VERSION 5.7 ;
  NOWIREEXTENSIONATPIN ON ;
  DIVIDERCHAR "/" ;
  BUSBITCHARS "[]" ;
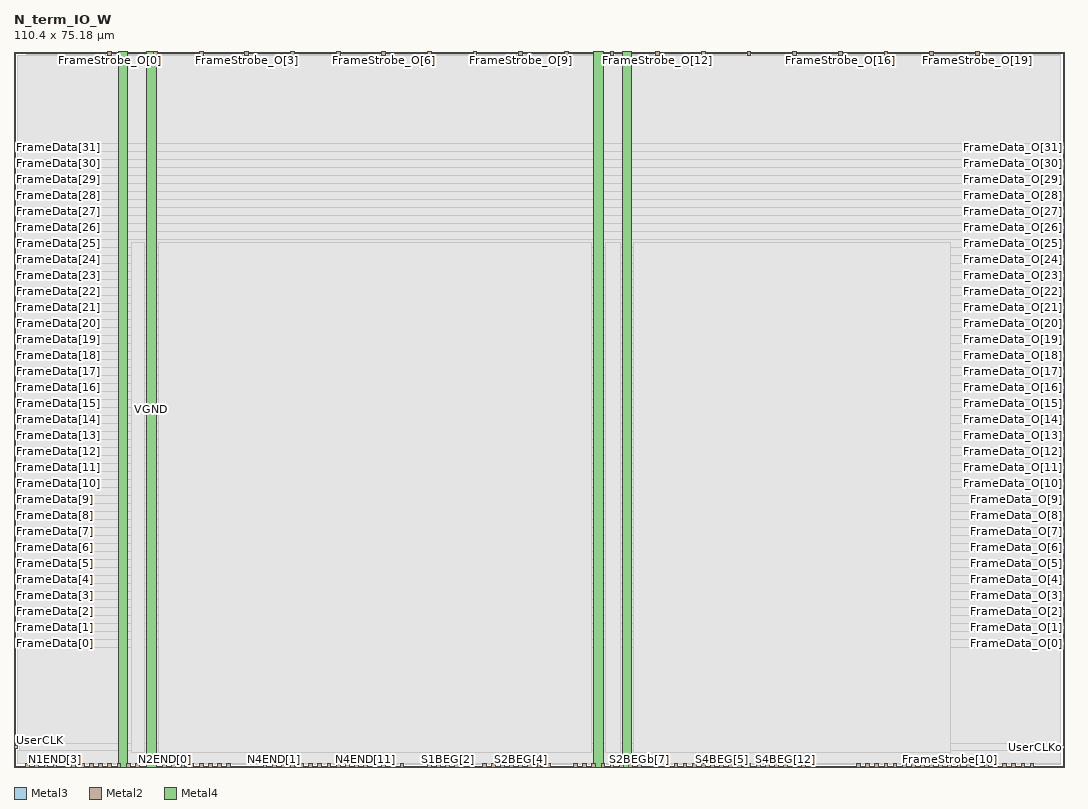
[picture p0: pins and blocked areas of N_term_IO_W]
MACRO N_term_IO_W
  CLASS BLOCK ;
  FOREIGN N_term_IO_W ;
  ORIGIN 0.000 0.000 ;
  SIZE 110.400 BY 75.180 ;
  PIN FrameData[0]
    DIRECTION INPUT ;
    USE SIGNAL ;
    ANTENNAGATEAREA 0.180700 ;
    ANTENNADIFFAREA 2.015400 ;
    PORT
      LAYER Metal3 ;
        RECT 0.000 12.820 0.400 13.220 ;
    END
  END FrameData[0]
  PIN FrameData[10]
    DIRECTION INPUT ;
    USE SIGNAL ;
    ANTENNAGATEAREA 0.180700 ;
    ANTENNADIFFAREA 2.015400 ;
    PORT
      LAYER Metal3 ;
        RECT 0.000 29.620 0.400 30.020 ;
    END
  END FrameData[10]
  PIN FrameData[11]
    DIRECTION INPUT ;
    USE SIGNAL ;
    ANTENNAGATEAREA 0.180700 ;
    ANTENNADIFFAREA 2.015400 ;
    PORT
      LAYER Metal3 ;
        RECT 0.000 31.300 0.400 31.700 ;
    END
  END FrameData[11]
  PIN FrameData[12]
    DIRECTION INPUT ;
    USE SIGNAL ;
    ANTENNAGATEAREA 0.180700 ;
    ANTENNADIFFAREA 2.015400 ;
    PORT
      LAYER Metal3 ;
        RECT 0.000 32.980 0.400 33.380 ;
    END
  END FrameData[12]
  PIN FrameData[13]
    DIRECTION INPUT ;
    USE SIGNAL ;
    ANTENNAGATEAREA 0.180700 ;
    ANTENNADIFFAREA 2.015400 ;
    PORT
      LAYER Metal3 ;
        RECT 0.000 34.660 0.400 35.060 ;
    END
  END FrameData[13]
  PIN FrameData[14]
    DIRECTION INPUT ;
    USE SIGNAL ;
    ANTENNAGATEAREA 0.180700 ;
    ANTENNADIFFAREA 2.015400 ;
    PORT
      LAYER Metal3 ;
        RECT 0.000 36.340 0.400 36.740 ;
    END
  END FrameData[14]
  PIN FrameData[15]
    DIRECTION INPUT ;
    USE SIGNAL ;
    ANTENNAGATEAREA 0.180700 ;
    ANTENNADIFFAREA 2.015400 ;
    PORT
      LAYER Metal3 ;
        RECT 0.000 38.020 0.400 38.420 ;
    END
  END FrameData[15]
  PIN FrameData[16]
    DIRECTION INPUT ;
    USE SIGNAL ;
    ANTENNAGATEAREA 0.180700 ;
    ANTENNADIFFAREA 2.015400 ;
    PORT
      LAYER Metal3 ;
        RECT 0.000 39.700 0.400 40.100 ;
    END
  END FrameData[16]
  PIN FrameData[17]
    DIRECTION INPUT ;
    USE SIGNAL ;
    ANTENNAGATEAREA 0.180700 ;
    ANTENNADIFFAREA 2.015400 ;
    PORT
      LAYER Metal3 ;
        RECT 0.000 41.380 0.400 41.780 ;
    END
  END FrameData[17]
  PIN FrameData[18]
    DIRECTION INPUT ;
    USE SIGNAL ;
    ANTENNAGATEAREA 0.180700 ;
    ANTENNADIFFAREA 2.015400 ;
    PORT
      LAYER Metal3 ;
        RECT 0.000 43.060 0.400 43.460 ;
    END
  END FrameData[18]
  PIN FrameData[19]
    DIRECTION INPUT ;
    USE SIGNAL ;
    ANTENNAGATEAREA 0.180700 ;
    ANTENNADIFFAREA 2.015400 ;
    PORT
      LAYER Metal3 ;
        RECT 0.000 44.740 0.400 45.140 ;
    END
  END FrameData[19]
  PIN FrameData[1]
    DIRECTION INPUT ;
    USE SIGNAL ;
    ANTENNAGATEAREA 0.180700 ;
    ANTENNADIFFAREA 2.015400 ;
    PORT
      LAYER Metal3 ;
        RECT 0.000 14.500 0.400 14.900 ;
    END
  END FrameData[1]
  PIN FrameData[20]
    DIRECTION INPUT ;
    USE SIGNAL ;
    ANTENNAGATEAREA 0.180700 ;
    ANTENNADIFFAREA 2.015400 ;
    PORT
      LAYER Metal3 ;
        RECT 0.000 46.420 0.400 46.820 ;
    END
  END FrameData[20]
  PIN FrameData[21]
    DIRECTION INPUT ;
    USE SIGNAL ;
    ANTENNAGATEAREA 0.180700 ;
    ANTENNADIFFAREA 2.015400 ;
    PORT
      LAYER Metal3 ;
        RECT 0.000 48.100 0.400 48.500 ;
    END
  END FrameData[21]
  PIN FrameData[22]
    DIRECTION INPUT ;
    USE SIGNAL ;
    ANTENNAGATEAREA 0.180700 ;
    ANTENNADIFFAREA 2.015400 ;
    PORT
      LAYER Metal3 ;
        RECT 0.000 49.780 0.400 50.180 ;
    END
  END FrameData[22]
  PIN FrameData[23]
    DIRECTION INPUT ;
    USE SIGNAL ;
    ANTENNAGATEAREA 0.180700 ;
    ANTENNADIFFAREA 2.015400 ;
    PORT
      LAYER Metal3 ;
        RECT 0.000 51.460 0.400 51.860 ;
    END
  END FrameData[23]
  PIN FrameData[24]
    DIRECTION INPUT ;
    USE SIGNAL ;
    ANTENNAGATEAREA 0.180700 ;
    ANTENNADIFFAREA 2.015400 ;
    PORT
      LAYER Metal3 ;
        RECT 0.000 53.140 0.400 53.540 ;
    END
  END FrameData[24]
  PIN FrameData[25]
    DIRECTION INPUT ;
    USE SIGNAL ;
    ANTENNAGATEAREA 0.180700 ;
    ANTENNADIFFAREA 2.015400 ;
    PORT
      LAYER Metal3 ;
        RECT 0.000 54.820 0.400 55.220 ;
    END
  END FrameData[25]
  PIN FrameData[26]
    DIRECTION INPUT ;
    USE SIGNAL ;
    ANTENNAGATEAREA 0.180700 ;
    ANTENNADIFFAREA 2.015400 ;
    PORT
      LAYER Metal3 ;
        RECT 0.000 56.500 0.400 56.900 ;
    END
  END FrameData[26]
  PIN FrameData[27]
    DIRECTION INPUT ;
    USE SIGNAL ;
    ANTENNAGATEAREA 0.180700 ;
    ANTENNADIFFAREA 2.015400 ;
    PORT
      LAYER Metal3 ;
        RECT 0.000 58.180 0.400 58.580 ;
    END
  END FrameData[27]
  PIN FrameData[28]
    DIRECTION INPUT ;
    USE SIGNAL ;
    ANTENNAGATEAREA 0.180700 ;
    ANTENNADIFFAREA 2.015400 ;
    PORT
      LAYER Metal3 ;
        RECT 0.000 59.860 0.400 60.260 ;
    END
  END FrameData[28]
  PIN FrameData[29]
    DIRECTION INPUT ;
    USE SIGNAL ;
    ANTENNAGATEAREA 0.180700 ;
    ANTENNADIFFAREA 2.015400 ;
    PORT
      LAYER Metal3 ;
        RECT 0.000 61.540 0.400 61.940 ;
    END
  END FrameData[29]
  PIN FrameData[2]
    DIRECTION INPUT ;
    USE SIGNAL ;
    ANTENNAGATEAREA 0.180700 ;
    ANTENNADIFFAREA 2.015400 ;
    PORT
      LAYER Metal3 ;
        RECT 0.000 16.180 0.400 16.580 ;
    END
  END FrameData[2]
  PIN FrameData[30]
    DIRECTION INPUT ;
    USE SIGNAL ;
    ANTENNAGATEAREA 0.180700 ;
    ANTENNADIFFAREA 2.015400 ;
    PORT
      LAYER Metal3 ;
        RECT 0.000 63.220 0.400 63.620 ;
    END
  END FrameData[30]
  PIN FrameData[31]
    DIRECTION INPUT ;
    USE SIGNAL ;
    ANTENNAGATEAREA 0.180700 ;
    ANTENNADIFFAREA 2.015400 ;
    PORT
      LAYER Metal3 ;
        RECT 0.000 64.900 0.400 65.300 ;
    END
  END FrameData[31]
  PIN FrameData[3]
    DIRECTION INPUT ;
    USE SIGNAL ;
    ANTENNAGATEAREA 0.180700 ;
    ANTENNADIFFAREA 2.015400 ;
    PORT
      LAYER Metal3 ;
        RECT 0.000 17.860 0.400 18.260 ;
    END
  END FrameData[3]
  PIN FrameData[4]
    DIRECTION INPUT ;
    USE SIGNAL ;
    ANTENNAGATEAREA 0.180700 ;
    ANTENNADIFFAREA 2.015400 ;
    PORT
      LAYER Metal3 ;
        RECT 0.000 19.540 0.400 19.940 ;
    END
  END FrameData[4]
  PIN FrameData[5]
    DIRECTION INPUT ;
    USE SIGNAL ;
    ANTENNAGATEAREA 0.180700 ;
    ANTENNADIFFAREA 2.015400 ;
    PORT
      LAYER Metal3 ;
        RECT 0.000 21.220 0.400 21.620 ;
    END
  END FrameData[5]
  PIN FrameData[6]
    DIRECTION INPUT ;
    USE SIGNAL ;
    ANTENNAGATEAREA 0.180700 ;
    ANTENNADIFFAREA 2.015400 ;
    PORT
      LAYER Metal3 ;
        RECT 0.000 22.900 0.400 23.300 ;
    END
  END FrameData[6]
  PIN FrameData[7]
    DIRECTION INPUT ;
    USE SIGNAL ;
    ANTENNAGATEAREA 0.180700 ;
    ANTENNADIFFAREA 2.015400 ;
    PORT
      LAYER Metal3 ;
        RECT 0.000 24.580 0.400 24.980 ;
    END
  END FrameData[7]
  PIN FrameData[8]
    DIRECTION INPUT ;
    USE SIGNAL ;
    ANTENNAGATEAREA 0.180700 ;
    ANTENNADIFFAREA 2.015400 ;
    PORT
      LAYER Metal3 ;
        RECT 0.000 26.260 0.400 26.660 ;
    END
  END FrameData[8]
  PIN FrameData[9]
    DIRECTION INPUT ;
    USE SIGNAL ;
    ANTENNAGATEAREA 0.180700 ;
    ANTENNADIFFAREA 2.015400 ;
    PORT
      LAYER Metal3 ;
        RECT 0.000 27.940 0.400 28.340 ;
    END
  END FrameData[9]
  PIN FrameData_O[0]
    DIRECTION OUTPUT ;
    USE SIGNAL ;
    ANTENNADIFFAREA 2.724000 ;
    PORT
      LAYER Metal3 ;
        RECT 110.000 12.820 110.400 13.220 ;
    END
  END FrameData_O[0]
  PIN FrameData_O[10]
    DIRECTION OUTPUT ;
    USE SIGNAL ;
    ANTENNADIFFAREA 2.724000 ;
    PORT
      LAYER Metal3 ;
        RECT 110.000 29.620 110.400 30.020 ;
    END
  END FrameData_O[10]
  PIN FrameData_O[11]
    DIRECTION OUTPUT ;
    USE SIGNAL ;
    ANTENNADIFFAREA 2.724000 ;
    PORT
      LAYER Metal3 ;
        RECT 110.000 31.300 110.400 31.700 ;
    END
  END FrameData_O[11]
  PIN FrameData_O[12]
    DIRECTION OUTPUT ;
    USE SIGNAL ;
    ANTENNADIFFAREA 2.724000 ;
    PORT
      LAYER Metal3 ;
        RECT 110.000 32.980 110.400 33.380 ;
    END
  END FrameData_O[12]
  PIN FrameData_O[13]
    DIRECTION OUTPUT ;
    USE SIGNAL ;
    ANTENNADIFFAREA 2.724000 ;
    PORT
      LAYER Metal3 ;
        RECT 110.000 34.660 110.400 35.060 ;
    END
  END FrameData_O[13]
  PIN FrameData_O[14]
    DIRECTION OUTPUT ;
    USE SIGNAL ;
    ANTENNADIFFAREA 2.724000 ;
    PORT
      LAYER Metal3 ;
        RECT 110.000 36.340 110.400 36.740 ;
    END
  END FrameData_O[14]
  PIN FrameData_O[15]
    DIRECTION OUTPUT ;
    USE SIGNAL ;
    ANTENNADIFFAREA 2.724000 ;
    PORT
      LAYER Metal3 ;
        RECT 110.000 38.020 110.400 38.420 ;
    END
  END FrameData_O[15]
  PIN FrameData_O[16]
    DIRECTION OUTPUT ;
    USE SIGNAL ;
    ANTENNADIFFAREA 2.724000 ;
    PORT
      LAYER Metal3 ;
        RECT 110.000 39.700 110.400 40.100 ;
    END
  END FrameData_O[16]
  PIN FrameData_O[17]
    DIRECTION OUTPUT ;
    USE SIGNAL ;
    ANTENNADIFFAREA 2.724000 ;
    PORT
      LAYER Metal3 ;
        RECT 110.000 41.380 110.400 41.780 ;
    END
  END FrameData_O[17]
  PIN FrameData_O[18]
    DIRECTION OUTPUT ;
    USE SIGNAL ;
    ANTENNADIFFAREA 2.724000 ;
    PORT
      LAYER Metal3 ;
        RECT 110.000 43.060 110.400 43.460 ;
    END
  END FrameData_O[18]
  PIN FrameData_O[19]
    DIRECTION OUTPUT ;
    USE SIGNAL ;
    ANTENNADIFFAREA 2.724000 ;
    PORT
      LAYER Metal3 ;
        RECT 110.000 44.740 110.400 45.140 ;
    END
  END FrameData_O[19]
  PIN FrameData_O[1]
    DIRECTION OUTPUT ;
    USE SIGNAL ;
    ANTENNADIFFAREA 2.724000 ;
    PORT
      LAYER Metal3 ;
        RECT 110.000 14.500 110.400 14.900 ;
    END
  END FrameData_O[1]
  PIN FrameData_O[20]
    DIRECTION OUTPUT ;
    USE SIGNAL ;
    ANTENNADIFFAREA 2.724000 ;
    PORT
      LAYER Metal3 ;
        RECT 110.000 46.420 110.400 46.820 ;
    END
  END FrameData_O[20]
  PIN FrameData_O[21]
    DIRECTION OUTPUT ;
    USE SIGNAL ;
    ANTENNADIFFAREA 2.724000 ;
    PORT
      LAYER Metal3 ;
        RECT 110.000 48.100 110.400 48.500 ;
    END
  END FrameData_O[21]
  PIN FrameData_O[22]
    DIRECTION OUTPUT ;
    USE SIGNAL ;
    ANTENNADIFFAREA 2.724000 ;
    PORT
      LAYER Metal3 ;
        RECT 110.000 49.780 110.400 50.180 ;
    END
  END FrameData_O[22]
  PIN FrameData_O[23]
    DIRECTION OUTPUT ;
    USE SIGNAL ;
    ANTENNADIFFAREA 2.724000 ;
    PORT
      LAYER Metal3 ;
        RECT 110.000 51.460 110.400 51.860 ;
    END
  END FrameData_O[23]
  PIN FrameData_O[24]
    DIRECTION OUTPUT ;
    USE SIGNAL ;
    ANTENNADIFFAREA 2.724000 ;
    PORT
      LAYER Metal3 ;
        RECT 110.000 53.140 110.400 53.540 ;
    END
  END FrameData_O[24]
  PIN FrameData_O[25]
    DIRECTION OUTPUT ;
    USE SIGNAL ;
    ANTENNADIFFAREA 2.724000 ;
    PORT
      LAYER Metal3 ;
        RECT 110.000 54.820 110.400 55.220 ;
    END
  END FrameData_O[25]
  PIN FrameData_O[26]
    DIRECTION OUTPUT ;
    USE SIGNAL ;
    ANTENNADIFFAREA 2.724000 ;
    PORT
      LAYER Metal3 ;
        RECT 110.000 56.500 110.400 56.900 ;
    END
  END FrameData_O[26]
  PIN FrameData_O[27]
    DIRECTION OUTPUT ;
    USE SIGNAL ;
    ANTENNADIFFAREA 2.724000 ;
    PORT
      LAYER Metal3 ;
        RECT 110.000 58.180 110.400 58.580 ;
    END
  END FrameData_O[27]
  PIN FrameData_O[28]
    DIRECTION OUTPUT ;
    USE SIGNAL ;
    ANTENNADIFFAREA 2.724000 ;
    PORT
      LAYER Metal3 ;
        RECT 110.000 59.860 110.400 60.260 ;
    END
  END FrameData_O[28]
  PIN FrameData_O[29]
    DIRECTION OUTPUT ;
    USE SIGNAL ;
    ANTENNADIFFAREA 2.724000 ;
    PORT
      LAYER Metal3 ;
        RECT 110.000 61.540 110.400 61.940 ;
    END
  END FrameData_O[29]
  PIN FrameData_O[2]
    DIRECTION OUTPUT ;
    USE SIGNAL ;
    ANTENNADIFFAREA 2.724000 ;
    PORT
      LAYER Metal3 ;
        RECT 110.000 16.180 110.400 16.580 ;
    END
  END FrameData_O[2]
  PIN FrameData_O[30]
    DIRECTION OUTPUT ;
    USE SIGNAL ;
    ANTENNADIFFAREA 2.724000 ;
    PORT
      LAYER Metal3 ;
        RECT 110.000 63.220 110.400 63.620 ;
    END
  END FrameData_O[30]
  PIN FrameData_O[31]
    DIRECTION OUTPUT ;
    USE SIGNAL ;
    ANTENNADIFFAREA 2.724000 ;
    PORT
      LAYER Metal3 ;
        RECT 110.000 64.900 110.400 65.300 ;
    END
  END FrameData_O[31]
  PIN FrameData_O[3]
    DIRECTION OUTPUT ;
    USE SIGNAL ;
    ANTENNADIFFAREA 2.724000 ;
    PORT
      LAYER Metal3 ;
        RECT 110.000 17.860 110.400 18.260 ;
    END
  END FrameData_O[3]
  PIN FrameData_O[4]
    DIRECTION OUTPUT ;
    USE SIGNAL ;
    ANTENNADIFFAREA 2.724000 ;
    PORT
      LAYER Metal3 ;
        RECT 110.000 19.540 110.400 19.940 ;
    END
  END FrameData_O[4]
  PIN FrameData_O[5]
    DIRECTION OUTPUT ;
    USE SIGNAL ;
    ANTENNADIFFAREA 2.724000 ;
    PORT
      LAYER Metal3 ;
        RECT 110.000 21.220 110.400 21.620 ;
    END
  END FrameData_O[5]
  PIN FrameData_O[6]
    DIRECTION OUTPUT ;
    USE SIGNAL ;
    ANTENNADIFFAREA 2.724000 ;
    PORT
      LAYER Metal3 ;
        RECT 110.000 22.900 110.400 23.300 ;
    END
  END FrameData_O[6]
  PIN FrameData_O[7]
    DIRECTION OUTPUT ;
    USE SIGNAL ;
    ANTENNADIFFAREA 2.724000 ;
    PORT
      LAYER Metal3 ;
        RECT 110.000 24.580 110.400 24.980 ;
    END
  END FrameData_O[7]
  PIN FrameData_O[8]
    DIRECTION OUTPUT ;
    USE SIGNAL ;
    ANTENNADIFFAREA 2.724000 ;
    PORT
      LAYER Metal3 ;
        RECT 110.000 26.260 110.400 26.660 ;
    END
  END FrameData_O[8]
  PIN FrameData_O[9]
    DIRECTION OUTPUT ;
    USE SIGNAL ;
    ANTENNADIFFAREA 2.724000 ;
    PORT
      LAYER Metal3 ;
        RECT 110.000 27.940 110.400 28.340 ;
    END
  END FrameData_O[9]
  PIN FrameStrobe[0]
    DIRECTION INPUT ;
    USE SIGNAL ;
    ANTENNAGATEAREA 0.180700 ;
    ANTENNADIFFAREA 2.015400 ;
    PORT
      LAYER Metal2 ;
        RECT 88.600 0.000 89.000 0.400 ;
    END
  END FrameStrobe[0]
  PIN FrameStrobe[10]
    DIRECTION INPUT ;
    USE SIGNAL ;
    ANTENNAGATEAREA 0.180700 ;
    ANTENNADIFFAREA 2.015400 ;
    PORT
      LAYER Metal2 ;
        RECT 98.200 0.000 98.600 0.400 ;
    END
  END FrameStrobe[10]
  PIN FrameStrobe[11]
    DIRECTION INPUT ;
    USE SIGNAL ;
    ANTENNAGATEAREA 0.180700 ;
    ANTENNADIFFAREA 2.015400 ;
    PORT
      LAYER Metal2 ;
        RECT 99.160 0.000 99.560 0.400 ;
    END
  END FrameStrobe[11]
  PIN FrameStrobe[12]
    DIRECTION INPUT ;
    USE SIGNAL ;
    ANTENNAGATEAREA 0.180700 ;
    ANTENNADIFFAREA 2.015400 ;
    PORT
      LAYER Metal2 ;
        RECT 100.120 0.000 100.520 0.400 ;
    END
  END FrameStrobe[12]
  PIN FrameStrobe[13]
    DIRECTION INPUT ;
    USE SIGNAL ;
    ANTENNAGATEAREA 0.180700 ;
    ANTENNADIFFAREA 2.015400 ;
    PORT
      LAYER Metal2 ;
        RECT 101.080 0.000 101.480 0.400 ;
    END
  END FrameStrobe[13]
  PIN FrameStrobe[14]
    DIRECTION INPUT ;
    USE SIGNAL ;
    ANTENNAGATEAREA 0.180700 ;
    ANTENNADIFFAREA 2.015400 ;
    PORT
      LAYER Metal2 ;
        RECT 102.040 0.000 102.440 0.400 ;
    END
  END FrameStrobe[14]
  PIN FrameStrobe[15]
    DIRECTION INPUT ;
    USE SIGNAL ;
    ANTENNAGATEAREA 0.180700 ;
    ANTENNADIFFAREA 2.015400 ;
    PORT
      LAYER Metal2 ;
        RECT 103.000 0.000 103.400 0.400 ;
    END
  END FrameStrobe[15]
  PIN FrameStrobe[16]
    DIRECTION INPUT ;
    USE SIGNAL ;
    ANTENNAGATEAREA 0.180700 ;
    ANTENNADIFFAREA 2.015400 ;
    PORT
      LAYER Metal2 ;
        RECT 103.960 0.000 104.360 0.400 ;
    END
  END FrameStrobe[16]
  PIN FrameStrobe[17]
    DIRECTION INPUT ;
    USE SIGNAL ;
    ANTENNAGATEAREA 0.180700 ;
    ANTENNADIFFAREA 2.015400 ;
    PORT
      LAYER Metal2 ;
        RECT 104.920 0.000 105.320 0.400 ;
    END
  END FrameStrobe[17]
  PIN FrameStrobe[18]
    DIRECTION INPUT ;
    USE SIGNAL ;
    ANTENNAGATEAREA 0.180700 ;
    ANTENNADIFFAREA 2.015400 ;
    PORT
      LAYER Metal2 ;
        RECT 105.880 0.000 106.280 0.400 ;
    END
  END FrameStrobe[18]
  PIN FrameStrobe[19]
    DIRECTION INPUT ;
    USE SIGNAL ;
    ANTENNAGATEAREA 0.180700 ;
    ANTENNADIFFAREA 2.015400 ;
    PORT
      LAYER Metal2 ;
        RECT 106.840 0.000 107.240 0.400 ;
    END
  END FrameStrobe[19]
  PIN FrameStrobe[1]
    DIRECTION INPUT ;
    USE SIGNAL ;
    ANTENNAGATEAREA 0.180700 ;
    ANTENNADIFFAREA 2.015400 ;
    PORT
      LAYER Metal2 ;
        RECT 89.560 0.000 89.960 0.400 ;
    END
  END FrameStrobe[1]
  PIN FrameStrobe[2]
    DIRECTION INPUT ;
    USE SIGNAL ;
    ANTENNAGATEAREA 0.180700 ;
    ANTENNADIFFAREA 2.015400 ;
    PORT
      LAYER Metal2 ;
        RECT 90.520 0.000 90.920 0.400 ;
    END
  END FrameStrobe[2]
  PIN FrameStrobe[3]
    DIRECTION INPUT ;
    USE SIGNAL ;
    ANTENNAGATEAREA 0.180700 ;
    ANTENNADIFFAREA 2.015400 ;
    PORT
      LAYER Metal2 ;
        RECT 91.480 0.000 91.880 0.400 ;
    END
  END FrameStrobe[3]
  PIN FrameStrobe[4]
    DIRECTION INPUT ;
    USE SIGNAL ;
    ANTENNAGATEAREA 0.180700 ;
    ANTENNADIFFAREA 2.015400 ;
    PORT
      LAYER Metal2 ;
        RECT 92.440 0.000 92.840 0.400 ;
    END
  END FrameStrobe[4]
  PIN FrameStrobe[5]
    DIRECTION INPUT ;
    USE SIGNAL ;
    ANTENNAGATEAREA 0.180700 ;
    ANTENNADIFFAREA 2.015400 ;
    PORT
      LAYER Metal2 ;
        RECT 93.400 0.000 93.800 0.400 ;
    END
  END FrameStrobe[5]
  PIN FrameStrobe[6]
    DIRECTION INPUT ;
    USE SIGNAL ;
    ANTENNAGATEAREA 0.180700 ;
    ANTENNADIFFAREA 2.015400 ;
    PORT
      LAYER Metal2 ;
        RECT 94.360 0.000 94.760 0.400 ;
    END
  END FrameStrobe[6]
  PIN FrameStrobe[7]
    DIRECTION INPUT ;
    USE SIGNAL ;
    ANTENNAGATEAREA 0.180700 ;
    ANTENNADIFFAREA 2.015400 ;
    PORT
      LAYER Metal2 ;
        RECT 95.320 0.000 95.720 0.400 ;
    END
  END FrameStrobe[7]
  PIN FrameStrobe[8]
    DIRECTION INPUT ;
    USE SIGNAL ;
    ANTENNAGATEAREA 0.180700 ;
    ANTENNADIFFAREA 2.015400 ;
    PORT
      LAYER Metal2 ;
        RECT 96.280 0.000 96.680 0.400 ;
    END
  END FrameStrobe[8]
  PIN FrameStrobe[9]
    DIRECTION INPUT ;
    USE SIGNAL ;
    ANTENNAGATEAREA 0.180700 ;
    ANTENNADIFFAREA 2.015400 ;
    PORT
      LAYER Metal2 ;
        RECT 97.240 0.000 97.640 0.400 ;
    END
  END FrameStrobe[9]
  PIN FrameStrobe_O[0]
    DIRECTION OUTPUT ;
    USE SIGNAL ;
    ANTENNADIFFAREA 2.724000 ;
    PORT
      LAYER Metal2 ;
        RECT 9.880 74.780 10.280 75.180 ;
    END
  END FrameStrobe_O[0]
  PIN FrameStrobe_O[10]
    DIRECTION OUTPUT ;
    USE SIGNAL ;
    ANTENNADIFFAREA 2.724000 ;
    PORT
      LAYER Metal2 ;
        RECT 57.880 74.780 58.280 75.180 ;
    END
  END FrameStrobe_O[10]
  PIN FrameStrobe_O[11]
    DIRECTION OUTPUT ;
    USE SIGNAL ;
    ANTENNADIFFAREA 2.724000 ;
    PORT
      LAYER Metal2 ;
        RECT 62.680 74.780 63.080 75.180 ;
    END
  END FrameStrobe_O[11]
  PIN FrameStrobe_O[12]
    DIRECTION OUTPUT ;
    USE SIGNAL ;
    ANTENNADIFFAREA 2.724000 ;
    PORT
      LAYER Metal2 ;
        RECT 67.480 74.780 67.880 75.180 ;
    END
  END FrameStrobe_O[12]
  PIN FrameStrobe_O[13]
    DIRECTION OUTPUT ;
    USE SIGNAL ;
    ANTENNADIFFAREA 2.724000 ;
    PORT
      LAYER Metal2 ;
        RECT 72.280 74.780 72.680 75.180 ;
    END
  END FrameStrobe_O[13]
  PIN FrameStrobe_O[14]
    DIRECTION OUTPUT ;
    USE SIGNAL ;
    ANTENNADIFFAREA 2.724000 ;
    PORT
      LAYER Metal2 ;
        RECT 77.080 74.780 77.480 75.180 ;
    END
  END FrameStrobe_O[14]
  PIN FrameStrobe_O[15]
    DIRECTION OUTPUT ;
    USE SIGNAL ;
    ANTENNADIFFAREA 2.724000 ;
    PORT
      LAYER Metal2 ;
        RECT 81.880 74.780 82.280 75.180 ;
    END
  END FrameStrobe_O[15]
  PIN FrameStrobe_O[16]
    DIRECTION OUTPUT ;
    USE SIGNAL ;
    ANTENNADIFFAREA 2.724000 ;
    PORT
      LAYER Metal2 ;
        RECT 86.680 74.780 87.080 75.180 ;
    END
  END FrameStrobe_O[16]
  PIN FrameStrobe_O[17]
    DIRECTION OUTPUT ;
    USE SIGNAL ;
    ANTENNADIFFAREA 2.724000 ;
    PORT
      LAYER Metal2 ;
        RECT 91.480 74.780 91.880 75.180 ;
    END
  END FrameStrobe_O[17]
  PIN FrameStrobe_O[18]
    DIRECTION OUTPUT ;
    USE SIGNAL ;
    ANTENNADIFFAREA 2.724000 ;
    PORT
      LAYER Metal2 ;
        RECT 96.280 74.780 96.680 75.180 ;
    END
  END FrameStrobe_O[18]
  PIN FrameStrobe_O[19]
    DIRECTION OUTPUT ;
    USE SIGNAL ;
    ANTENNADIFFAREA 2.724000 ;
    PORT
      LAYER Metal2 ;
        RECT 101.080 74.780 101.480 75.180 ;
    END
  END FrameStrobe_O[19]
  PIN FrameStrobe_O[1]
    DIRECTION OUTPUT ;
    USE SIGNAL ;
    ANTENNADIFFAREA 2.724000 ;
    PORT
      LAYER Metal2 ;
        RECT 14.680 74.780 15.080 75.180 ;
    END
  END FrameStrobe_O[1]
  PIN FrameStrobe_O[2]
    DIRECTION OUTPUT ;
    USE SIGNAL ;
    ANTENNADIFFAREA 2.724000 ;
    PORT
      LAYER Metal2 ;
        RECT 19.480 74.780 19.880 75.180 ;
    END
  END FrameStrobe_O[2]
  PIN FrameStrobe_O[3]
    DIRECTION OUTPUT ;
    USE SIGNAL ;
    ANTENNADIFFAREA 2.724000 ;
    PORT
      LAYER Metal2 ;
        RECT 24.280 74.780 24.680 75.180 ;
    END
  END FrameStrobe_O[3]
  PIN FrameStrobe_O[4]
    DIRECTION OUTPUT ;
    USE SIGNAL ;
    ANTENNADIFFAREA 2.724000 ;
    PORT
      LAYER Metal2 ;
        RECT 29.080 74.780 29.480 75.180 ;
    END
  END FrameStrobe_O[4]
  PIN FrameStrobe_O[5]
    DIRECTION OUTPUT ;
    USE SIGNAL ;
    ANTENNADIFFAREA 2.724000 ;
    PORT
      LAYER Metal2 ;
        RECT 33.880 74.780 34.280 75.180 ;
    END
  END FrameStrobe_O[5]
  PIN FrameStrobe_O[6]
    DIRECTION OUTPUT ;
    USE SIGNAL ;
    ANTENNADIFFAREA 2.724000 ;
    PORT
      LAYER Metal2 ;
        RECT 38.680 74.780 39.080 75.180 ;
    END
  END FrameStrobe_O[6]
  PIN FrameStrobe_O[7]
    DIRECTION OUTPUT ;
    USE SIGNAL ;
    ANTENNADIFFAREA 2.724000 ;
    PORT
      LAYER Metal2 ;
        RECT 43.480 74.780 43.880 75.180 ;
    END
  END FrameStrobe_O[7]
  PIN FrameStrobe_O[8]
    DIRECTION OUTPUT ;
    USE SIGNAL ;
    ANTENNADIFFAREA 2.724000 ;
    PORT
      LAYER Metal2 ;
        RECT 48.280 74.780 48.680 75.180 ;
    END
  END FrameStrobe_O[8]
  PIN FrameStrobe_O[9]
    DIRECTION OUTPUT ;
    USE SIGNAL ;
    ANTENNADIFFAREA 2.724000 ;
    PORT
      LAYER Metal2 ;
        RECT 53.080 74.780 53.480 75.180 ;
    END
  END FrameStrobe_O[9]
  PIN N1END[0]
    DIRECTION INPUT ;
    USE SIGNAL ;
    ANTENNAGATEAREA 0.180700 ;
    ANTENNADIFFAREA 2.015400 ;
    PORT
      LAYER Metal2 ;
        RECT 1.240 0.000 1.640 0.400 ;
    END
  END N1END[0]
  PIN N1END[1]
    DIRECTION INPUT ;
    USE SIGNAL ;
    ANTENNAGATEAREA 0.180700 ;
    ANTENNADIFFAREA 2.015400 ;
    PORT
      LAYER Metal2 ;
        RECT 2.200 0.000 2.600 0.400 ;
    END
  END N1END[1]
  PIN N1END[2]
    DIRECTION INPUT ;
    USE SIGNAL ;
    ANTENNAGATEAREA 0.180700 ;
    ANTENNADIFFAREA 2.015400 ;
    PORT
      LAYER Metal2 ;
        RECT 3.160 0.000 3.560 0.400 ;
    END
  END N1END[2]
  PIN N1END[3]
    DIRECTION INPUT ;
    USE SIGNAL ;
    ANTENNAGATEAREA 0.180700 ;
    ANTENNADIFFAREA 2.015400 ;
    PORT
      LAYER Metal2 ;
        RECT 4.120 0.000 4.520 0.400 ;
    END
  END N1END[3]
  PIN N2END[0]
    DIRECTION INPUT ;
    USE SIGNAL ;
    ANTENNAGATEAREA 0.180700 ;
    ANTENNADIFFAREA 2.015400 ;
    PORT
      LAYER Metal2 ;
        RECT 15.640 0.000 16.040 0.400 ;
    END
  END N2END[0]
  PIN N2END[1]
    DIRECTION INPUT ;
    USE SIGNAL ;
    ANTENNAGATEAREA 0.180700 ;
    ANTENNADIFFAREA 2.015400 ;
    PORT
      LAYER Metal2 ;
        RECT 16.600 0.000 17.000 0.400 ;
    END
  END N2END[1]
  PIN N2END[2]
    DIRECTION INPUT ;
    USE SIGNAL ;
    ANTENNAGATEAREA 0.180700 ;
    ANTENNADIFFAREA 2.015400 ;
    PORT
      LAYER Metal2 ;
        RECT 17.560 0.000 17.960 0.400 ;
    END
  END N2END[2]
  PIN N2END[3]
    DIRECTION INPUT ;
    USE SIGNAL ;
    ANTENNAGATEAREA 0.180700 ;
    ANTENNADIFFAREA 2.015400 ;
    PORT
      LAYER Metal2 ;
        RECT 18.520 0.000 18.920 0.400 ;
    END
  END N2END[3]
  PIN N2END[4]
    DIRECTION INPUT ;
    USE SIGNAL ;
    ANTENNAGATEAREA 0.180700 ;
    ANTENNADIFFAREA 2.015400 ;
    PORT
      LAYER Metal2 ;
        RECT 19.480 0.000 19.880 0.400 ;
    END
  END N2END[4]
  PIN N2END[5]
    DIRECTION INPUT ;
    USE SIGNAL ;
    ANTENNAGATEAREA 0.180700 ;
    ANTENNADIFFAREA 2.015400 ;
    PORT
      LAYER Metal2 ;
        RECT 20.440 0.000 20.840 0.400 ;
    END
  END N2END[5]
  PIN N2END[6]
    DIRECTION INPUT ;
    USE SIGNAL ;
    ANTENNAGATEAREA 0.180700 ;
    ANTENNADIFFAREA 2.015400 ;
    PORT
      LAYER Metal2 ;
        RECT 21.400 0.000 21.800 0.400 ;
    END
  END N2END[6]
  PIN N2END[7]
    DIRECTION INPUT ;
    USE SIGNAL ;
    ANTENNAGATEAREA 0.180700 ;
    ANTENNADIFFAREA 2.015400 ;
    PORT
      LAYER Metal2 ;
        RECT 22.360 0.000 22.760 0.400 ;
    END
  END N2END[7]
  PIN N2MID[0]
    DIRECTION INPUT ;
    USE SIGNAL ;
    ANTENNAGATEAREA 0.180700 ;
    ANTENNADIFFAREA 2.015400 ;
    PORT
      LAYER Metal2 ;
        RECT 6.040 0.000 6.440 0.400 ;
    END
  END N2MID[0]
  PIN N2MID[1]
    DIRECTION INPUT ;
    USE SIGNAL ;
    ANTENNAGATEAREA 0.180700 ;
    ANTENNADIFFAREA 2.015400 ;
    PORT
      LAYER Metal2 ;
        RECT 7.000 0.000 7.400 0.400 ;
    END
  END N2MID[1]
  PIN N2MID[2]
    DIRECTION INPUT ;
    USE SIGNAL ;
    ANTENNAGATEAREA 0.180700 ;
    ANTENNADIFFAREA 2.015400 ;
    PORT
      LAYER Metal2 ;
        RECT 7.960 0.000 8.360 0.400 ;
    END
  END N2MID[2]
  PIN N2MID[3]
    DIRECTION INPUT ;
    USE SIGNAL ;
    ANTENNAGATEAREA 0.180700 ;
    ANTENNADIFFAREA 2.015400 ;
    PORT
      LAYER Metal2 ;
        RECT 8.920 0.000 9.320 0.400 ;
    END
  END N2MID[3]
  PIN N2MID[4]
    DIRECTION INPUT ;
    USE SIGNAL ;
    ANTENNAGATEAREA 0.180700 ;
    ANTENNADIFFAREA 2.015400 ;
    PORT
      LAYER Metal2 ;
        RECT 9.880 0.000 10.280 0.400 ;
    END
  END N2MID[4]
  PIN N2MID[5]
    DIRECTION INPUT ;
    USE SIGNAL ;
    ANTENNAGATEAREA 0.180700 ;
    ANTENNADIFFAREA 2.015400 ;
    PORT
      LAYER Metal2 ;
        RECT 10.840 0.000 11.240 0.400 ;
    END
  END N2MID[5]
  PIN N2MID[6]
    DIRECTION INPUT ;
    USE SIGNAL ;
    ANTENNAGATEAREA 0.180700 ;
    ANTENNADIFFAREA 2.015400 ;
    PORT
      LAYER Metal2 ;
        RECT 11.800 0.000 12.200 0.400 ;
    END
  END N2MID[6]
  PIN N2MID[7]
    DIRECTION INPUT ;
    USE SIGNAL ;
    ANTENNAGATEAREA 0.180700 ;
    ANTENNADIFFAREA 2.015400 ;
    PORT
      LAYER Metal2 ;
        RECT 12.760 0.000 13.160 0.400 ;
    END
  END N2MID[7]
  PIN N4END[0]
    DIRECTION INPUT ;
    USE SIGNAL ;
    ANTENNAGATEAREA 0.180700 ;
    ANTENNADIFFAREA 2.015400 ;
    PORT
      LAYER Metal2 ;
        RECT 26.200 0.000 26.600 0.400 ;
    END
  END N4END[0]
  PIN N4END[10]
    DIRECTION INPUT ;
    USE SIGNAL ;
    ANTENNAGATEAREA 0.180700 ;
    ANTENNADIFFAREA 2.015400 ;
    PORT
      LAYER Metal2 ;
        RECT 35.800 0.000 36.200 0.400 ;
    END
  END N4END[10]
  PIN N4END[11]
    DIRECTION INPUT ;
    USE SIGNAL ;
    ANTENNAGATEAREA 0.180700 ;
    ANTENNADIFFAREA 2.015400 ;
    PORT
      LAYER Metal2 ;
        RECT 36.760 0.000 37.160 0.400 ;
    END
  END N4END[11]
  PIN N4END[12]
    DIRECTION INPUT ;
    USE SIGNAL ;
    ANTENNAGATEAREA 0.180700 ;
    ANTENNADIFFAREA 2.015400 ;
    PORT
      LAYER Metal2 ;
        RECT 37.720 0.000 38.120 0.400 ;
    END
  END N4END[12]
  PIN N4END[13]
    DIRECTION INPUT ;
    USE SIGNAL ;
    ANTENNAGATEAREA 0.180700 ;
    ANTENNADIFFAREA 2.015400 ;
    PORT
      LAYER Metal2 ;
        RECT 38.680 0.000 39.080 0.400 ;
    END
  END N4END[13]
  PIN N4END[14]
    DIRECTION INPUT ;
    USE SIGNAL ;
    ANTENNAGATEAREA 0.180700 ;
    ANTENNADIFFAREA 2.015400 ;
    PORT
      LAYER Metal2 ;
        RECT 39.640 0.000 40.040 0.400 ;
    END
  END N4END[14]
  PIN N4END[15]
    DIRECTION INPUT ;
    USE SIGNAL ;
    ANTENNAGATEAREA 0.180700 ;
    ANTENNADIFFAREA 2.015400 ;
    PORT
      LAYER Metal2 ;
        RECT 40.600 0.000 41.000 0.400 ;
    END
  END N4END[15]
  PIN N4END[1]
    DIRECTION INPUT ;
    USE SIGNAL ;
    ANTENNAGATEAREA 0.180700 ;
    ANTENNADIFFAREA 2.015400 ;
    PORT
      LAYER Metal2 ;
        RECT 27.160 0.000 27.560 0.400 ;
    END
  END N4END[1]
  PIN N4END[2]
    DIRECTION INPUT ;
    USE SIGNAL ;
    ANTENNAGATEAREA 0.180700 ;
    ANTENNADIFFAREA 2.015400 ;
    PORT
      LAYER Metal2 ;
        RECT 28.120 0.000 28.520 0.400 ;
    END
  END N4END[2]
  PIN N4END[3]
    DIRECTION INPUT ;
    USE SIGNAL ;
    ANTENNAGATEAREA 0.180700 ;
    ANTENNADIFFAREA 2.015400 ;
    PORT
      LAYER Metal2 ;
        RECT 29.080 0.000 29.480 0.400 ;
    END
  END N4END[3]
  PIN N4END[4]
    DIRECTION INPUT ;
    USE SIGNAL ;
    ANTENNAGATEAREA 0.180700 ;
    ANTENNADIFFAREA 2.015400 ;
    PORT
      LAYER Metal2 ;
        RECT 30.040 0.000 30.440 0.400 ;
    END
  END N4END[4]
  PIN N4END[5]
    DIRECTION INPUT ;
    USE SIGNAL ;
    ANTENNAGATEAREA 0.180700 ;
    ANTENNADIFFAREA 2.015400 ;
    PORT
      LAYER Metal2 ;
        RECT 31.000 0.000 31.400 0.400 ;
    END
  END N4END[5]
  PIN N4END[6]
    DIRECTION INPUT ;
    USE SIGNAL ;
    ANTENNAGATEAREA 0.180700 ;
    ANTENNADIFFAREA 2.015400 ;
    PORT
      LAYER Metal2 ;
        RECT 31.960 0.000 32.360 0.400 ;
    END
  END N4END[6]
  PIN N4END[7]
    DIRECTION INPUT ;
    USE SIGNAL ;
    ANTENNAGATEAREA 0.180700 ;
    ANTENNADIFFAREA 2.015400 ;
    PORT
      LAYER Metal2 ;
        RECT 32.920 0.000 33.320 0.400 ;
    END
  END N4END[7]
  PIN N4END[8]
    DIRECTION INPUT ;
    USE SIGNAL ;
    ANTENNAGATEAREA 0.180700 ;
    ANTENNADIFFAREA 2.015400 ;
    PORT
      LAYER Metal2 ;
        RECT 33.880 0.000 34.280 0.400 ;
    END
  END N4END[8]
  PIN N4END[9]
    DIRECTION INPUT ;
    USE SIGNAL ;
    ANTENNAGATEAREA 0.180700 ;
    ANTENNADIFFAREA 2.015400 ;
    PORT
      LAYER Metal2 ;
        RECT 34.840 0.000 35.240 0.400 ;
    END
  END N4END[9]
  PIN S1BEG[0]
    DIRECTION OUTPUT ;
    USE SIGNAL ;
    ANTENNADIFFAREA 2.724000 ;
    PORT
      LAYER Metal2 ;
        RECT 43.480 0.000 43.880 0.400 ;
    END
  END S1BEG[0]
  PIN S1BEG[1]
    DIRECTION OUTPUT ;
    USE SIGNAL ;
    ANTENNADIFFAREA 2.724000 ;
    PORT
      LAYER Metal2 ;
        RECT 44.440 0.000 44.840 0.400 ;
    END
  END S1BEG[1]
  PIN S1BEG[2]
    DIRECTION OUTPUT ;
    USE SIGNAL ;
    ANTENNADIFFAREA 2.724000 ;
    PORT
      LAYER Metal2 ;
        RECT 45.400 0.000 45.800 0.400 ;
    END
  END S1BEG[2]
  PIN S1BEG[3]
    DIRECTION OUTPUT ;
    USE SIGNAL ;
    ANTENNADIFFAREA 2.724000 ;
    PORT
      LAYER Metal2 ;
        RECT 46.360 0.000 46.760 0.400 ;
    END
  END S1BEG[3]
  PIN S2BEG[0]
    DIRECTION OUTPUT ;
    USE SIGNAL ;
    ANTENNADIFFAREA 2.724000 ;
    PORT
      LAYER Metal2 ;
        RECT 49.240 0.000 49.640 0.400 ;
    END
  END S2BEG[0]
  PIN S2BEG[1]
    DIRECTION OUTPUT ;
    USE SIGNAL ;
    ANTENNADIFFAREA 2.724000 ;
    PORT
      LAYER Metal2 ;
        RECT 50.200 0.000 50.600 0.400 ;
    END
  END S2BEG[1]
  PIN S2BEG[2]
    DIRECTION OUTPUT ;
    USE SIGNAL ;
    ANTENNADIFFAREA 2.724000 ;
    PORT
      LAYER Metal2 ;
        RECT 51.160 0.000 51.560 0.400 ;
    END
  END S2BEG[2]
  PIN S2BEG[3]
    DIRECTION OUTPUT ;
    USE SIGNAL ;
    ANTENNADIFFAREA 2.724000 ;
    PORT
      LAYER Metal2 ;
        RECT 52.120 0.000 52.520 0.400 ;
    END
  END S2BEG[3]
  PIN S2BEG[4]
    DIRECTION OUTPUT ;
    USE SIGNAL ;
    ANTENNADIFFAREA 2.724000 ;
    PORT
      LAYER Metal2 ;
        RECT 53.080 0.000 53.480 0.400 ;
    END
  END S2BEG[4]
  PIN S2BEG[5]
    DIRECTION OUTPUT ;
    USE SIGNAL ;
    ANTENNADIFFAREA 2.724000 ;
    PORT
      LAYER Metal2 ;
        RECT 54.040 0.000 54.440 0.400 ;
    END
  END S2BEG[5]
  PIN S2BEG[6]
    DIRECTION OUTPUT ;
    USE SIGNAL ;
    ANTENNADIFFAREA 2.724000 ;
    PORT
      LAYER Metal2 ;
        RECT 55.000 0.000 55.400 0.400 ;
    END
  END S2BEG[6]
  PIN S2BEG[7]
    DIRECTION OUTPUT ;
    USE SIGNAL ;
    ANTENNADIFFAREA 2.724000 ;
    PORT
      LAYER Metal2 ;
        RECT 55.960 0.000 56.360 0.400 ;
    END
  END S2BEG[7]
  PIN S2BEGb[0]
    DIRECTION OUTPUT ;
    USE SIGNAL ;
    ANTENNADIFFAREA 2.724000 ;
    PORT
      LAYER Metal2 ;
        RECT 58.840 0.000 59.240 0.400 ;
    END
  END S2BEGb[0]
  PIN S2BEGb[1]
    DIRECTION OUTPUT ;
    USE SIGNAL ;
    ANTENNADIFFAREA 2.724000 ;
    PORT
      LAYER Metal2 ;
        RECT 59.800 0.000 60.200 0.400 ;
    END
  END S2BEGb[1]
  PIN S2BEGb[2]
    DIRECTION OUTPUT ;
    USE SIGNAL ;
    ANTENNADIFFAREA 2.724000 ;
    PORT
      LAYER Metal2 ;
        RECT 60.760 0.000 61.160 0.400 ;
    END
  END S2BEGb[2]
  PIN S2BEGb[3]
    DIRECTION OUTPUT ;
    USE SIGNAL ;
    ANTENNADIFFAREA 2.724000 ;
    PORT
      LAYER Metal2 ;
        RECT 61.720 0.000 62.120 0.400 ;
    END
  END S2BEGb[3]
  PIN S2BEGb[4]
    DIRECTION OUTPUT ;
    USE SIGNAL ;
    ANTENNADIFFAREA 2.724000 ;
    PORT
      LAYER Metal2 ;
        RECT 62.680 0.000 63.080 0.400 ;
    END
  END S2BEGb[4]
  PIN S2BEGb[5]
    DIRECTION OUTPUT ;
    USE SIGNAL ;
    ANTENNADIFFAREA 2.724000 ;
    PORT
      LAYER Metal2 ;
        RECT 63.640 0.000 64.040 0.400 ;
    END
  END S2BEGb[5]
  PIN S2BEGb[6]
    DIRECTION OUTPUT ;
    USE SIGNAL ;
    ANTENNADIFFAREA 2.724000 ;
    PORT
      LAYER Metal2 ;
        RECT 64.600 0.000 65.000 0.400 ;
    END
  END S2BEGb[6]
  PIN S2BEGb[7]
    DIRECTION OUTPUT ;
    USE SIGNAL ;
    ANTENNADIFFAREA 2.724000 ;
    PORT
      LAYER Metal2 ;
        RECT 65.560 0.000 65.960 0.400 ;
    END
  END S2BEGb[7]
  PIN S4BEG[0]
    DIRECTION OUTPUT ;
    USE SIGNAL ;
    ANTENNADIFFAREA 2.724000 ;
    PORT
      LAYER Metal2 ;
        RECT 69.400 0.000 69.800 0.400 ;
    END
  END S4BEG[0]
  PIN S4BEG[10]
    DIRECTION OUTPUT ;
    USE SIGNAL ;
    ANTENNADIFFAREA 2.724000 ;
    PORT
      LAYER Metal2 ;
        RECT 79.000 0.000 79.400 0.400 ;
    END
  END S4BEG[10]
  PIN S4BEG[11]
    DIRECTION OUTPUT ;
    USE SIGNAL ;
    ANTENNADIFFAREA 2.724000 ;
    PORT
      LAYER Metal2 ;
        RECT 79.960 0.000 80.360 0.400 ;
    END
  END S4BEG[11]
  PIN S4BEG[12]
    DIRECTION OUTPUT ;
    USE SIGNAL ;
    ANTENNADIFFAREA 2.724000 ;
    PORT
      LAYER Metal2 ;
        RECT 80.920 0.000 81.320 0.400 ;
    END
  END S4BEG[12]
  PIN S4BEG[13]
    DIRECTION OUTPUT ;
    USE SIGNAL ;
    ANTENNADIFFAREA 2.724000 ;
    PORT
      LAYER Metal2 ;
        RECT 81.880 0.000 82.280 0.400 ;
    END
  END S4BEG[13]
  PIN S4BEG[14]
    DIRECTION OUTPUT ;
    USE SIGNAL ;
    ANTENNADIFFAREA 2.724000 ;
    PORT
      LAYER Metal2 ;
        RECT 82.840 0.000 83.240 0.400 ;
    END
  END S4BEG[14]
  PIN S4BEG[15]
    DIRECTION OUTPUT ;
    USE SIGNAL ;
    ANTENNADIFFAREA 2.724000 ;
    PORT
      LAYER Metal2 ;
        RECT 83.800 0.000 84.200 0.400 ;
    END
  END S4BEG[15]
  PIN S4BEG[1]
    DIRECTION OUTPUT ;
    USE SIGNAL ;
    ANTENNADIFFAREA 2.724000 ;
    PORT
      LAYER Metal2 ;
        RECT 70.360 0.000 70.760 0.400 ;
    END
  END S4BEG[1]
  PIN S4BEG[2]
    DIRECTION OUTPUT ;
    USE SIGNAL ;
    ANTENNADIFFAREA 2.724000 ;
    PORT
      LAYER Metal2 ;
        RECT 71.320 0.000 71.720 0.400 ;
    END
  END S4BEG[2]
  PIN S4BEG[3]
    DIRECTION OUTPUT ;
    USE SIGNAL ;
    ANTENNADIFFAREA 2.724000 ;
    PORT
      LAYER Metal2 ;
        RECT 72.280 0.000 72.680 0.400 ;
    END
  END S4BEG[3]
  PIN S4BEG[4]
    DIRECTION OUTPUT ;
    USE SIGNAL ;
    ANTENNADIFFAREA 2.724000 ;
    PORT
      LAYER Metal2 ;
        RECT 73.240 0.000 73.640 0.400 ;
    END
  END S4BEG[4]
  PIN S4BEG[5]
    DIRECTION OUTPUT ;
    USE SIGNAL ;
    ANTENNADIFFAREA 2.724000 ;
    PORT
      LAYER Metal2 ;
        RECT 74.200 0.000 74.600 0.400 ;
    END
  END S4BEG[5]
  PIN S4BEG[6]
    DIRECTION OUTPUT ;
    USE SIGNAL ;
    ANTENNADIFFAREA 2.724000 ;
    PORT
      LAYER Metal2 ;
        RECT 75.160 0.000 75.560 0.400 ;
    END
  END S4BEG[6]
  PIN S4BEG[7]
    DIRECTION OUTPUT ;
    USE SIGNAL ;
    ANTENNADIFFAREA 2.724000 ;
    PORT
      LAYER Metal2 ;
        RECT 76.120 0.000 76.520 0.400 ;
    END
  END S4BEG[7]
  PIN S4BEG[8]
    DIRECTION OUTPUT ;
    USE SIGNAL ;
    ANTENNADIFFAREA 2.724000 ;
    PORT
      LAYER Metal2 ;
        RECT 77.080 0.000 77.480 0.400 ;
    END
  END S4BEG[8]
  PIN S4BEG[9]
    DIRECTION OUTPUT ;
    USE SIGNAL ;
    ANTENNADIFFAREA 2.724000 ;
    PORT
      LAYER Metal2 ;
        RECT 78.040 0.000 78.440 0.400 ;
    END
  END S4BEG[9]
  PIN UserCLK
    DIRECTION INPUT ;
    USE SIGNAL ;
    ANTENNAGATEAREA 1.450800 ;
    PORT
      LAYER Metal3 ;
        RECT 0.000 1.900 0.400 2.300 ;
    END
  END UserCLK
  PIN UserCLKo
    DIRECTION OUTPUT ;
    USE SIGNAL ;
    ANTENNADIFFAREA 2.724000 ;
    PORT
      LAYER Metal3 ;
        RECT 110.000 1.900 110.400 2.300 ;
    END
  END UserCLKo
  PIN VGND
    DIRECTION INOUT ;
    USE GROUND ;
    PORT
      LAYER Metal4 ;
        RECT 13.940 0.000 14.940 75.180 ;
    END
    PORT
      LAYER Metal4 ;
        RECT 63.940 0.000 64.940 75.180 ;
    END
  END VGND
  PIN VPWR
    DIRECTION INOUT ;
    USE POWER ;
    PORT
      LAYER Metal4 ;
        RECT 10.940 0.000 11.940 75.180 ;
    END
    PORT
      LAYER Metal4 ;
        RECT 60.940 0.000 61.940 75.180 ;
    END
  END VPWR
  OBS
      LAYER GatPoly ;
        RECT 1.440 3.630 108.960 68.190 ;
      LAYER Metal1 ;
        RECT 1.440 3.560 108.960 68.260 ;
      LAYER Metal2 ;
        RECT 1.335 74.570 9.670 74.905 ;
        RECT 10.490 74.570 14.470 74.905 ;
        RECT 15.290 74.570 19.270 74.905 ;
        RECT 20.090 74.570 24.070 74.905 ;
        RECT 24.890 74.570 28.870 74.905 ;
        RECT 29.690 74.570 33.670 74.905 ;
        RECT 34.490 74.570 38.470 74.905 ;
        RECT 39.290 74.570 43.270 74.905 ;
        RECT 44.090 74.570 48.070 74.905 ;
        RECT 48.890 74.570 52.870 74.905 ;
        RECT 53.690 74.570 57.670 74.905 ;
        RECT 58.490 74.570 62.470 74.905 ;
        RECT 63.290 74.570 67.270 74.905 ;
        RECT 68.090 74.570 72.070 74.905 ;
        RECT 72.890 74.570 76.870 74.905 ;
        RECT 77.690 74.570 81.670 74.905 ;
        RECT 82.490 74.570 86.470 74.905 ;
        RECT 87.290 74.570 91.270 74.905 ;
        RECT 92.090 74.570 96.070 74.905 ;
        RECT 96.890 74.570 100.870 74.905 ;
        RECT 101.690 74.570 110.025 74.905 ;
        RECT 1.335 0.610 110.025 74.570 ;
        RECT 1.850 0.275 1.990 0.610 ;
        RECT 2.810 0.275 2.950 0.610 ;
        RECT 3.770 0.275 3.910 0.610 ;
        RECT 4.730 0.275 5.830 0.610 ;
        RECT 6.650 0.275 6.790 0.610 ;
        RECT 7.610 0.275 7.750 0.610 ;
        RECT 8.570 0.275 8.710 0.610 ;
        RECT 9.530 0.275 9.670 0.610 ;
        RECT 10.490 0.275 10.630 0.610 ;
        RECT 11.450 0.275 11.590 0.610 ;
        RECT 12.410 0.275 12.550 0.610 ;
        RECT 13.370 0.275 15.430 0.610 ;
        RECT 16.250 0.275 16.390 0.610 ;
        RECT 17.210 0.275 17.350 0.610 ;
        RECT 18.170 0.275 18.310 0.610 ;
        RECT 19.130 0.275 19.270 0.610 ;
        RECT 20.090 0.275 20.230 0.610 ;
        RECT 21.050 0.275 21.190 0.610 ;
        RECT 22.010 0.275 22.150 0.610 ;
        RECT 22.970 0.275 25.990 0.610 ;
        RECT 26.810 0.275 26.950 0.610 ;
        RECT 27.770 0.275 27.910 0.610 ;
        RECT 28.730 0.275 28.870 0.610 ;
        RECT 29.690 0.275 29.830 0.610 ;
        RECT 30.650 0.275 30.790 0.610 ;
        RECT 31.610 0.275 31.750 0.610 ;
        RECT 32.570 0.275 32.710 0.610 ;
        RECT 33.530 0.275 33.670 0.610 ;
        RECT 34.490 0.275 34.630 0.610 ;
        RECT 35.450 0.275 35.590 0.610 ;
        RECT 36.410 0.275 36.550 0.610 ;
        RECT 37.370 0.275 37.510 0.610 ;
        RECT 38.330 0.275 38.470 0.610 ;
        RECT 39.290 0.275 39.430 0.610 ;
        RECT 40.250 0.275 40.390 0.610 ;
        RECT 41.210 0.275 43.270 0.610 ;
        RECT 44.090 0.275 44.230 0.610 ;
        RECT 45.050 0.275 45.190 0.610 ;
        RECT 46.010 0.275 46.150 0.610 ;
        RECT 46.970 0.275 49.030 0.610 ;
        RECT 49.850 0.275 49.990 0.610 ;
        RECT 50.810 0.275 50.950 0.610 ;
        RECT 51.770 0.275 51.910 0.610 ;
        RECT 52.730 0.275 52.870 0.610 ;
        RECT 53.690 0.275 53.830 0.610 ;
        RECT 54.650 0.275 54.790 0.610 ;
        RECT 55.610 0.275 55.750 0.610 ;
        RECT 56.570 0.275 58.630 0.610 ;
        RECT 59.450 0.275 59.590 0.610 ;
        RECT 60.410 0.275 60.550 0.610 ;
        RECT 61.370 0.275 61.510 0.610 ;
        RECT 62.330 0.275 62.470 0.610 ;
        RECT 63.290 0.275 63.430 0.610 ;
        RECT 64.250 0.275 64.390 0.610 ;
        RECT 65.210 0.275 65.350 0.610 ;
        RECT 66.170 0.275 69.190 0.610 ;
        RECT 70.010 0.275 70.150 0.610 ;
        RECT 70.970 0.275 71.110 0.610 ;
        RECT 71.930 0.275 72.070 0.610 ;
        RECT 72.890 0.275 73.030 0.610 ;
        RECT 73.850 0.275 73.990 0.610 ;
        RECT 74.810 0.275 74.950 0.610 ;
        RECT 75.770 0.275 75.910 0.610 ;
        RECT 76.730 0.275 76.870 0.610 ;
        RECT 77.690 0.275 77.830 0.610 ;
        RECT 78.650 0.275 78.790 0.610 ;
        RECT 79.610 0.275 79.750 0.610 ;
        RECT 80.570 0.275 80.710 0.610 ;
        RECT 81.530 0.275 81.670 0.610 ;
        RECT 82.490 0.275 82.630 0.610 ;
        RECT 83.450 0.275 83.590 0.610 ;
        RECT 84.410 0.275 88.390 0.610 ;
        RECT 89.210 0.275 89.350 0.610 ;
        RECT 90.170 0.275 90.310 0.610 ;
        RECT 91.130 0.275 91.270 0.610 ;
        RECT 92.090 0.275 92.230 0.610 ;
        RECT 93.050 0.275 93.190 0.610 ;
        RECT 94.010 0.275 94.150 0.610 ;
        RECT 94.970 0.275 95.110 0.610 ;
        RECT 95.930 0.275 96.070 0.610 ;
        RECT 96.890 0.275 97.030 0.610 ;
        RECT 97.850 0.275 97.990 0.610 ;
        RECT 98.810 0.275 98.950 0.610 ;
        RECT 99.770 0.275 99.910 0.610 ;
        RECT 100.730 0.275 100.870 0.610 ;
        RECT 101.690 0.275 101.830 0.610 ;
        RECT 102.650 0.275 102.790 0.610 ;
        RECT 103.610 0.275 103.750 0.610 ;
        RECT 104.570 0.275 104.710 0.610 ;
        RECT 105.530 0.275 105.670 0.610 ;
        RECT 106.490 0.275 106.630 0.610 ;
        RECT 107.450 0.275 110.025 0.610 ;
      LAYER Metal3 ;
        RECT 0.380 65.510 110.065 74.860 ;
        RECT 0.610 64.690 109.790 65.510 ;
        RECT 0.380 63.830 110.065 64.690 ;
        RECT 0.610 63.010 109.790 63.830 ;
        RECT 0.380 62.150 110.065 63.010 ;
        RECT 0.610 61.330 109.790 62.150 ;
        RECT 0.380 60.470 110.065 61.330 ;
        RECT 0.610 59.650 109.790 60.470 ;
        RECT 0.380 58.790 110.065 59.650 ;
        RECT 0.610 57.970 109.790 58.790 ;
        RECT 0.380 57.110 110.065 57.970 ;
        RECT 0.610 56.290 109.790 57.110 ;
        RECT 0.380 55.430 110.065 56.290 ;
        RECT 0.610 54.610 109.790 55.430 ;
        RECT 0.380 53.750 110.065 54.610 ;
        RECT 0.610 52.930 109.790 53.750 ;
        RECT 0.380 52.070 110.065 52.930 ;
        RECT 0.610 51.250 109.790 52.070 ;
        RECT 0.380 50.390 110.065 51.250 ;
        RECT 0.610 49.570 109.790 50.390 ;
        RECT 0.380 48.710 110.065 49.570 ;
        RECT 0.610 47.890 109.790 48.710 ;
        RECT 0.380 47.030 110.065 47.890 ;
        RECT 0.610 46.210 109.790 47.030 ;
        RECT 0.380 45.350 110.065 46.210 ;
        RECT 0.610 44.530 109.790 45.350 ;
        RECT 0.380 43.670 110.065 44.530 ;
        RECT 0.610 42.850 109.790 43.670 ;
        RECT 0.380 41.990 110.065 42.850 ;
        RECT 0.610 41.170 109.790 41.990 ;
        RECT 0.380 40.310 110.065 41.170 ;
        RECT 0.610 39.490 109.790 40.310 ;
        RECT 0.380 38.630 110.065 39.490 ;
        RECT 0.610 37.810 109.790 38.630 ;
        RECT 0.380 36.950 110.065 37.810 ;
        RECT 0.610 36.130 109.790 36.950 ;
        RECT 0.380 35.270 110.065 36.130 ;
        RECT 0.610 34.450 109.790 35.270 ;
        RECT 0.380 33.590 110.065 34.450 ;
        RECT 0.610 32.770 109.790 33.590 ;
        RECT 0.380 31.910 110.065 32.770 ;
        RECT 0.610 31.090 109.790 31.910 ;
        RECT 0.380 30.230 110.065 31.090 ;
        RECT 0.610 29.410 109.790 30.230 ;
        RECT 0.380 28.550 110.065 29.410 ;
        RECT 0.610 27.730 109.790 28.550 ;
        RECT 0.380 26.870 110.065 27.730 ;
        RECT 0.610 26.050 109.790 26.870 ;
        RECT 0.380 25.190 110.065 26.050 ;
        RECT 0.610 24.370 109.790 25.190 ;
        RECT 0.380 23.510 110.065 24.370 ;
        RECT 0.610 22.690 109.790 23.510 ;
        RECT 0.380 21.830 110.065 22.690 ;
        RECT 0.610 21.010 109.790 21.830 ;
        RECT 0.380 20.150 110.065 21.010 ;
        RECT 0.610 19.330 109.790 20.150 ;
        RECT 0.380 18.470 110.065 19.330 ;
        RECT 0.610 17.650 109.790 18.470 ;
        RECT 0.380 16.790 110.065 17.650 ;
        RECT 0.610 15.970 109.790 16.790 ;
        RECT 0.380 15.110 110.065 15.970 ;
        RECT 0.610 14.290 109.790 15.110 ;
        RECT 0.380 13.430 110.065 14.290 ;
        RECT 0.610 12.610 109.790 13.430 ;
        RECT 0.380 2.510 110.065 12.610 ;
        RECT 0.610 1.690 109.790 2.510 ;
        RECT 0.380 0.320 110.065 1.690 ;
      LAYER Metal4 ;
        RECT 12.380 1.535 13.730 55.165 ;
        RECT 15.150 1.535 60.730 55.165 ;
        RECT 62.150 1.535 63.730 55.165 ;
        RECT 65.150 1.535 98.500 55.165 ;
  END
END N_term_IO_W
END LIBRARY

